VERSION 5.7 ;
  NOWIREEXTENSIONATPIN ON ;
  DIVIDERCHAR "/" ;
  BUSBITCHARS "[]" ;
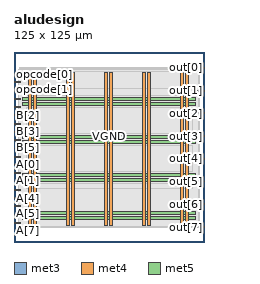
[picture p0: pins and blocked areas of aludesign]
MACRO aludesign
  CLASS BLOCK ;
  FOREIGN aludesign ;
  ORIGIN 0.000 0.000 ;
  SIZE 125.000 BY 125.000 ;
  PIN A[0]
    DIRECTION INPUT ;
    USE SIGNAL ;
    ANTENNAGATEAREA 0.247500 ;
    PORT
      LAYER met3 ;
        RECT 0.000 50.360 4.000 50.960 ;
    END
  END A[0]
  PIN A[1]
    DIRECTION INPUT ;
    USE SIGNAL ;
    ANTENNAGATEAREA 0.213000 ;
    PORT
      LAYER met3 ;
        RECT 0.000 44.920 4.000 45.520 ;
    END
  END A[1]
  PIN A[2]
    DIRECTION INPUT ;
    USE SIGNAL ;
    ANTENNAGATEAREA 0.247500 ;
    PORT
      LAYER met3 ;
        RECT 0.000 39.480 4.000 40.080 ;
    END
  END A[2]
  PIN A[3]
    DIRECTION INPUT ;
    USE SIGNAL ;
    ANTENNAGATEAREA 0.247500 ;
    PORT
      LAYER met3 ;
        RECT 0.000 34.040 4.000 34.640 ;
    END
  END A[3]
  PIN A[4]
    DIRECTION INPUT ;
    USE SIGNAL ;
    ANTENNAGATEAREA 0.495000 ;
    PORT
      LAYER met3 ;
        RECT 0.000 28.600 4.000 29.200 ;
    END
  END A[4]
  PIN A[5]
    DIRECTION INPUT ;
    USE SIGNAL ;
    ANTENNAGATEAREA 0.159000 ;
    PORT
      LAYER met3 ;
        RECT 0.000 23.160 4.000 23.760 ;
    END
  END A[5]
  PIN A[6]
    DIRECTION INPUT ;
    USE SIGNAL ;
    ANTENNAGATEAREA 0.495000 ;
    PORT
      LAYER met3 ;
        RECT 0.000 17.720 4.000 18.320 ;
    END
  END A[6]
  PIN A[7]
    DIRECTION INPUT ;
    USE SIGNAL ;
    ANTENNAGATEAREA 0.213000 ;
    PORT
      LAYER met3 ;
        RECT 0.000 12.280 4.000 12.880 ;
    END
  END A[7]
  PIN B[0]
    DIRECTION INPUT ;
    USE SIGNAL ;
    ANTENNAGATEAREA 0.495000 ;
    PORT
      LAYER met3 ;
        RECT 0.000 93.880 4.000 94.480 ;
    END
  END B[0]
  PIN B[1]
    DIRECTION INPUT ;
    USE SIGNAL ;
    ANTENNAGATEAREA 0.742500 ;
    PORT
      LAYER met3 ;
        RECT 0.000 88.440 4.000 89.040 ;
    END
  END B[1]
  PIN B[2]
    DIRECTION INPUT ;
    USE SIGNAL ;
    ANTENNAGATEAREA 0.213000 ;
    PORT
      LAYER met3 ;
        RECT 0.000 83.000 4.000 83.600 ;
    END
  END B[2]
  PIN B[3]
    DIRECTION INPUT ;
    USE SIGNAL ;
    ANTENNAGATEAREA 0.213000 ;
    PORT
      LAYER met3 ;
        RECT 0.000 77.560 4.000 78.160 ;
    END
  END B[3]
  PIN B[4]
    DIRECTION INPUT ;
    USE SIGNAL ;
    ANTENNAGATEAREA 0.159000 ;
    PORT
      LAYER met3 ;
        RECT 0.000 72.120 4.000 72.720 ;
    END
  END B[4]
  PIN B[5]
    DIRECTION INPUT ;
    USE SIGNAL ;
    ANTENNAGATEAREA 0.247500 ;
    PORT
      LAYER met3 ;
        RECT 0.000 66.680 4.000 67.280 ;
    END
  END B[5]
  PIN B[6]
    DIRECTION INPUT ;
    USE SIGNAL ;
    ANTENNAGATEAREA 0.247500 ;
    PORT
      LAYER met3 ;
        RECT 0.000 61.240 4.000 61.840 ;
    END
  END B[6]
  PIN B[7]
    DIRECTION INPUT ;
    USE SIGNAL ;
    ANTENNAGATEAREA 0.159000 ;
    PORT
      LAYER met3 ;
        RECT 0.000 55.800 4.000 56.400 ;
    END
  END B[7]
  PIN VGND
    DIRECTION INOUT ;
    USE GROUND ;
    PORT
      LAYER met4 ;
        RECT 13.020 10.640 14.620 111.760 ;
    END
    PORT
      LAYER met4 ;
        RECT 38.020 10.640 39.620 111.760 ;
    END
    PORT
      LAYER met4 ;
        RECT 63.020 10.640 64.620 111.760 ;
    END
    PORT
      LAYER met4 ;
        RECT 88.020 10.640 89.620 111.760 ;
    END
    PORT
      LAYER met4 ;
        RECT 113.020 10.640 114.620 111.760 ;
    END
    PORT
      LAYER met5 ;
        RECT 5.280 18.380 119.380 19.980 ;
    END
    PORT
      LAYER met5 ;
        RECT 5.280 43.380 119.380 44.980 ;
    END
    PORT
      LAYER met5 ;
        RECT 5.280 68.380 119.380 69.980 ;
    END
    PORT
      LAYER met5 ;
        RECT 5.280 93.380 119.380 94.980 ;
    END
  END VGND
  PIN VPWR
    DIRECTION INOUT ;
    USE POWER ;
    PORT
      LAYER met4 ;
        RECT 9.720 10.640 11.320 111.760 ;
    END
    PORT
      LAYER met4 ;
        RECT 34.720 10.640 36.320 111.760 ;
    END
    PORT
      LAYER met4 ;
        RECT 59.720 10.640 61.320 111.760 ;
    END
    PORT
      LAYER met4 ;
        RECT 84.720 10.640 86.320 111.760 ;
    END
    PORT
      LAYER met4 ;
        RECT 109.720 10.640 111.320 111.760 ;
    END
    PORT
      LAYER met5 ;
        RECT 5.280 15.080 119.380 16.680 ;
    END
    PORT
      LAYER met5 ;
        RECT 5.280 40.080 119.380 41.680 ;
    END
    PORT
      LAYER met5 ;
        RECT 5.280 65.080 119.380 66.680 ;
    END
    PORT
      LAYER met5 ;
        RECT 5.280 90.080 119.380 91.680 ;
    END
  END VPWR
  PIN opcode[0]
    DIRECTION INPUT ;
    USE SIGNAL ;
    ANTENNAGATEAREA 0.159000 ;
    PORT
      LAYER met3 ;
        RECT 0.000 110.200 4.000 110.800 ;
    END
  END opcode[0]
  PIN opcode[1]
    DIRECTION INPUT ;
    USE SIGNAL ;
    ANTENNAGATEAREA 0.213000 ;
    PORT
      LAYER met3 ;
        RECT 0.000 104.760 4.000 105.360 ;
    END
  END opcode[1]
  PIN opcode[2]
    DIRECTION INPUT ;
    USE SIGNAL ;
    ANTENNAGATEAREA 0.247500 ;
    PORT
      LAYER met3 ;
        RECT 0.000 99.320 4.000 99.920 ;
    END
  END opcode[2]
  PIN out[0]
    DIRECTION OUTPUT ;
    USE SIGNAL ;
    ANTENNADIFFAREA 0.445500 ;
    PORT
      LAYER met3 ;
        RECT 121.000 114.280 125.000 114.880 ;
    END
  END out[0]
  PIN out[1]
    DIRECTION OUTPUT ;
    USE SIGNAL ;
    ANTENNADIFFAREA 0.445500 ;
    PORT
      LAYER met3 ;
        RECT 121.000 99.320 125.000 99.920 ;
    END
  END out[1]
  PIN out[2]
    DIRECTION OUTPUT ;
    USE SIGNAL ;
    ANTENNADIFFAREA 0.445500 ;
    PORT
      LAYER met3 ;
        RECT 121.000 84.360 125.000 84.960 ;
    END
  END out[2]
  PIN out[3]
    DIRECTION OUTPUT ;
    USE SIGNAL ;
    ANTENNADIFFAREA 0.445500 ;
    PORT
      LAYER met3 ;
        RECT 121.000 69.400 125.000 70.000 ;
    END
  END out[3]
  PIN out[4]
    DIRECTION OUTPUT ;
    USE SIGNAL ;
    ANTENNADIFFAREA 0.445500 ;
    PORT
      LAYER met3 ;
        RECT 121.000 54.440 125.000 55.040 ;
    END
  END out[4]
  PIN out[5]
    DIRECTION OUTPUT ;
    USE SIGNAL ;
    ANTENNADIFFAREA 0.445500 ;
    PORT
      LAYER met3 ;
        RECT 121.000 39.480 125.000 40.080 ;
    END
  END out[5]
  PIN out[6]
    DIRECTION OUTPUT ;
    USE SIGNAL ;
    ANTENNADIFFAREA 1.336500 ;
    PORT
      LAYER met3 ;
        RECT 121.000 24.520 125.000 25.120 ;
    END
  END out[6]
  PIN out[7]
    DIRECTION OUTPUT ;
    USE SIGNAL ;
    ANTENNADIFFAREA 1.782000 ;
    PORT
      LAYER met3 ;
        RECT 121.000 9.560 125.000 10.160 ;
    END
  END out[7]
  OBS
      LAYER nwell ;
        RECT 5.330 10.795 119.330 111.710 ;
      LAYER li1 ;
        RECT 5.520 10.795 119.140 111.605 ;
      LAYER met1 ;
        RECT 3.750 9.900 122.290 111.760 ;
      LAYER met2 ;
        RECT 3.780 9.675 122.260 114.765 ;
      LAYER met3 ;
        RECT 3.950 113.880 120.600 114.745 ;
        RECT 3.950 111.200 121.170 113.880 ;
        RECT 4.400 109.800 121.170 111.200 ;
        RECT 3.950 105.760 121.170 109.800 ;
        RECT 4.400 104.360 121.170 105.760 ;
        RECT 3.950 100.320 121.170 104.360 ;
        RECT 4.400 98.920 120.600 100.320 ;
        RECT 3.950 94.880 121.170 98.920 ;
        RECT 4.400 93.480 121.170 94.880 ;
        RECT 3.950 89.440 121.170 93.480 ;
        RECT 4.400 88.040 121.170 89.440 ;
        RECT 3.950 85.360 121.170 88.040 ;
        RECT 3.950 84.000 120.600 85.360 ;
        RECT 4.400 83.960 120.600 84.000 ;
        RECT 4.400 82.600 121.170 83.960 ;
        RECT 3.950 78.560 121.170 82.600 ;
        RECT 4.400 77.160 121.170 78.560 ;
        RECT 3.950 73.120 121.170 77.160 ;
        RECT 4.400 71.720 121.170 73.120 ;
        RECT 3.950 70.400 121.170 71.720 ;
        RECT 3.950 69.000 120.600 70.400 ;
        RECT 3.950 67.680 121.170 69.000 ;
        RECT 4.400 66.280 121.170 67.680 ;
        RECT 3.950 62.240 121.170 66.280 ;
        RECT 4.400 60.840 121.170 62.240 ;
        RECT 3.950 56.800 121.170 60.840 ;
        RECT 4.400 55.440 121.170 56.800 ;
        RECT 4.400 55.400 120.600 55.440 ;
        RECT 3.950 54.040 120.600 55.400 ;
        RECT 3.950 51.360 121.170 54.040 ;
        RECT 4.400 49.960 121.170 51.360 ;
        RECT 3.950 45.920 121.170 49.960 ;
        RECT 4.400 44.520 121.170 45.920 ;
        RECT 3.950 40.480 121.170 44.520 ;
        RECT 4.400 39.080 120.600 40.480 ;
        RECT 3.950 35.040 121.170 39.080 ;
        RECT 4.400 33.640 121.170 35.040 ;
        RECT 3.950 29.600 121.170 33.640 ;
        RECT 4.400 28.200 121.170 29.600 ;
        RECT 3.950 25.520 121.170 28.200 ;
        RECT 3.950 24.160 120.600 25.520 ;
        RECT 4.400 24.120 120.600 24.160 ;
        RECT 4.400 22.760 121.170 24.120 ;
        RECT 3.950 18.720 121.170 22.760 ;
        RECT 4.400 17.320 121.170 18.720 ;
        RECT 3.950 13.280 121.170 17.320 ;
        RECT 4.400 11.880 121.170 13.280 ;
        RECT 3.950 10.560 121.170 11.880 ;
        RECT 3.950 9.695 120.600 10.560 ;
      LAYER met4 ;
        RECT 3.070 112.160 121.145 113.385 ;
        RECT 3.070 10.240 9.320 112.160 ;
        RECT 11.720 10.240 12.620 112.160 ;
        RECT 15.020 10.240 34.320 112.160 ;
        RECT 36.720 10.240 37.620 112.160 ;
        RECT 40.020 10.240 59.320 112.160 ;
        RECT 61.720 10.240 62.620 112.160 ;
        RECT 65.020 10.240 84.320 112.160 ;
        RECT 86.720 10.240 87.620 112.160 ;
        RECT 90.020 10.240 109.320 112.160 ;
        RECT 111.720 10.240 112.620 112.160 ;
        RECT 115.020 10.240 121.145 112.160 ;
        RECT 3.070 9.695 121.145 10.240 ;
      LAYER met5 ;
        RECT 7.940 96.580 117.180 101.100 ;
        RECT 7.940 71.580 117.180 88.480 ;
        RECT 7.940 46.580 117.180 63.480 ;
        RECT 7.940 34.900 117.180 38.480 ;
  END
END aludesign
END LIBRARY

